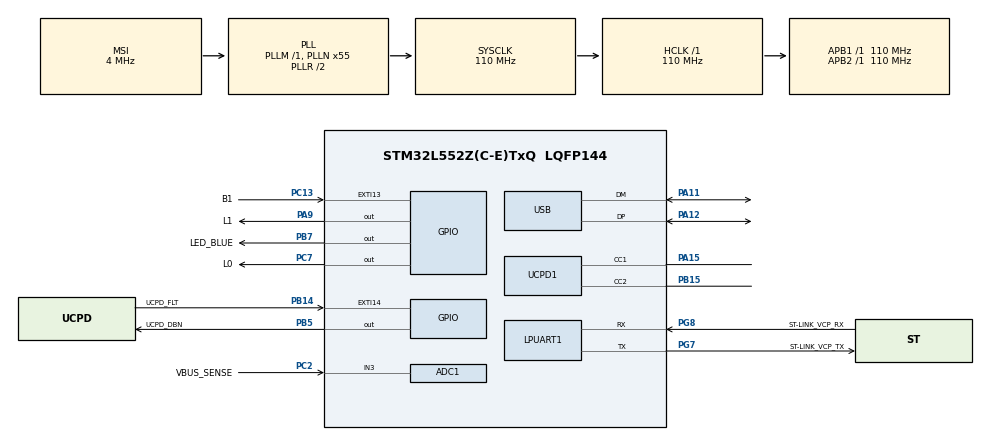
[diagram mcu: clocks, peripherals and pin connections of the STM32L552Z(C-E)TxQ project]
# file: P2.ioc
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ADC1.Channel-0\#ChannelRegularConversion=ADC_CHANNEL_3
ADC1.NbrOfConversionFlag=1
ADC1.OffsetNumber-0\#ChannelRegularConversion=ADC_OFFSET_NONE
ADC1.Rank-0\#ChannelRegularConversion=1
ADC1.SamplingTime-0\#ChannelRegularConversion=ADC_SAMPLETIME_2CYCLES_5
ADC1.master=1
Mcu.Family=STM32L5
Mcu.Name=STM32L552Z(C-E)TxQ
Mcu.Package=LQFP144
Mcu.TrustZone=disable
NVIC.EXTI13_IRQn=true\:0\:0\:false\:false\:true\:true\:true\:true
NVIC.PriorityGroup=NVIC_PRIORITYGROUP_3
PA11.Mode=Device
PA11.Signal=USB_DM
PA12.Mode=Device
PA12.Signal=USB_DP
PA13\ (JTMS/SWDIO).Mode=Trace_Asynchronous_SW
PA13\ (JTMS/SWDIO).Signal=DEBUG_JTMS-SWDIO
PA14\ (JTCK/SWCLK).Mode=Trace_Asynchronous_SW
PA14\ (JTCK/SWCLK).Signal=DEBUG_JTCK-SWCLK
PA15\ (JTDI).Mode=Source_AllSignals
PA15\ (JTDI).Signal=UCPD1_CC1
PA9.GPIO_Label=L1
PA9.Signal=GPIO_Output
PB14.GPIO_Label=UCPD_FLT
PB14.Signal=GPXTI14
PB15.Mode=Source_AllSignals
PB15.Signal=UCPD1_CC2
PB3\ (JTDO/TRACESWO).Mode=Trace_Asynchronous_SW
PB3\ (JTDO/TRACESWO).Signal=DEBUG_JTDO-SWO
PB5.GPIO_Label=UCPD_DBN
PB5.Signal=GPIO_Output
PB7.GPIO_Label=LED_BLUE
PB7.Signal=GPIO_Output
PC13.GPIO_Label=B1
PC13.Signal=GPXTI13
PC14-OSC32_IN\ (PC14).Mode=LSE-External-Oscillator
PC14-OSC32_IN\ (PC14).Signal=RCC_OSC32_IN
PC15-OSC32_OUT\ (PC15).Mode=LSE-External-Oscillator
PC15-OSC32_OUT\ (PC15).Signal=RCC_OSC32_OUT
PC2.GPIO_Label=VBUS_SENSE
PC2.Signal=ADCx_IN3
PC7.GPIO_Label=L0
PC7.Signal=GPIO_Output
PG7.GPIO_Label=ST-LINK_VCP_TX
PG7.Mode=Asynchronous
PG7.Signal=LPUART1_TX
PG8.GPIO_Label=ST-LINK_VCP_RX
PG8.Mode=Asynchronous
PG8.Signal=LPUART1_RX
ProjectManager.HeapSize=0x200
ProjectManager.StackSize=0x400
ProjectManager.TargetToolchain=STM32CubeIDE
RCC.ADCCLockSelection=RCC_ADCCLKSOURCE_SYSCLK
RCC.ADCFreq_Value=110000000
RCC.AHBFreq_Value=110000000
RCC.APB1Freq_Value=110000000
RCC.APB1TimFreq_Value=110000000
RCC.APB2Freq_Value=110000000
RCC.APB2TimFreq_Value=110000000
RCC.CK48CLockSelection=RCC_USBCLKSOURCE_HSI48
RCC.CortexFreq_Value=110000000
RCC.HCLKFreq_Value=110000000
RCC.HSE_VALUE=8000000
RCC.HSI48_VALUE=48000000
RCC.HSI_VALUE=16000000
RCC.MSI_VALUE=4000000
RCC.PLLN=55
RCC.PLLSAI1N=24
RCC.RTCClockSelection=RCC_RTCCLKSOURCE_LSE
RCC.SYSCLKFreq_VALUE=110000000
RCC.SYSCLKSource=RCC_SYSCLKSOURCE_PLLCLK
RCC.USBFreq_Value=48000000
RCC.VCOOutputFreq_Value=220000000
SH.ADCx_IN3.0=ADC1_IN3,IN3-Single-Ended
VP_ICACHE_VS_ICACHE.Mode=DirectMappedCache
VP_PWR_VS_DBSignals.Mode=DisableDeadBatterySignals
VP_RTC_VS_RTC_Activate.Mode=RTC_Enabled
board=NUCLEO-L552ZE-Q

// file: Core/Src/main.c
/* USER CODE BEGIN Header */
/**
  ******************************************************************************
  * @file           : main.c
  * @brief          : Main program body
  ******************************************************************************
  * @attention
  *
  * Copyright (c) 2024 STMicroelectronics.
  * All rights reserved.
  *
  * This software is licensed under terms that can be found in the LICENSE file
  * in the root directory of this software component.
  * If no LICENSE file comes with this software, it is provided AS-IS.
  *
  ******************************************************************************
  */
/* USER CODE END Header */
#include "main.h"

ADC_HandleTypeDef hadc1;

UART_HandleTypeDef hlpuart1;

RTC_HandleTypeDef hrtc;

PCD_HandleTypeDef hpcd_USB_FS;

/* USER CODE BEGIN PV */

uint8_t interrupcion0=0; //var que refleJa la interrupcion causada por la activacion de B0

uint8_t interrupcion1=0;//var que refleJa la interrupcion causada por la activacion de B1

int estado = 0; //var para almacenar estado en el que  se encuentra la ejecucion

/* USER CODE END PV */

void SystemClock_Config(void);
static void MX_GPIO_Init(void);
static void MX_ADC1_Init(void);
static void MX_ICACHE_Init(void);
static void MX_LPUART1_UART_Init(void);
static void MX_RTC_Init(void);
static void MX_UCPD1_Init(void);
static void MX_USB_PCD_Init(void);

int main(void)
{

  /* MCU Configuration--------------------------------------------------------*/

  /* Reset of all peripherals, Initializes the Flash interface and the Systick. */
  HAL_Init();

  /* Configure the system clock */
  SystemClock_Config();

  /* Initialize all configured peripherals */
  MX_GPIO_Init();
  MX_ADC1_Init();
  MX_ICACHE_Init();
  MX_LPUART1_UART_Init();
  MX_RTC_Init();
  MX_UCPD1_Init();
  MX_USB_PCD_Init();

  /* Infinite loop */
  /* USER CODE BEGIN WHILE */
  while (1)
  {
	  //cambios de estado segun estado actual para B0=1; B1=0
	  if(interrupcion0==1){
		  if(estado==0){
			  estado=3;
		  }else if(estado==1){
			  estado=0;
		  }else if(estado==2){
			  estado=1;
		  }else if(estado==3){
			  estado=2;
		  }
		  interrupcion0=0;

	  }else if(interrupcion1==1){//cambios de estado segun estado actual para B0=0; B1=1

		  if(estado==0){
			  estado=1;
		  }else if(estado==1){
			  estado=2;
		  }else if(estado==2){
			  estado=3;
		  }else if(estado==3){
			  estado=0;
		  }
		  interrupcion1=0;

	  }

	  //acciones para cada estado
	  if(estado==0){
		  //L0=0; L1=1
		  HAL_GPIO_WritePin(L0_GPIO_Port, L0_Pin, GPIO_PIN_RESET);
		  HAL_GPIO_WritePin(L1_GPIO_Port, L1_Pin, GPIO_PIN_SET);

	  }else if(estado==1){
		  //L0=1; L1=0
		  HAL_GPIO_WritePin(L0_GPIO_Port, L0_Pin, GPIO_PIN_SET);
		  HAL_GPIO_WritePin(L1_GPIO_Port, L1_Pin, GPIO_PIN_RESET);

	  }else if(estado==2){
		  //L0=1; L1=1
		  HAL_GPIO_WritePin(L0_GPIO_Port, L0_Pin, GPIO_PIN_SET);
		  HAL_GPIO_WritePin(L1_GPIO_Port, L1_Pin, GPIO_PIN_SET);

	  }else if(estado==3){
		  //L0=0; L1=0
		  HAL_GPIO_WritePin(L0_GPIO_Port, L0_Pin, GPIO_PIN_RESET);
		  HAL_GPIO_WritePin(L1_GPIO_Port, L1_Pin, GPIO_PIN_RESET);

	  }
    /* USER CODE END WHILE */

  }
}

void SystemClock_Config(void)
{
  RCC_OscInitTypeDef RCC_OscInitStruct = {0};
  RCC_ClkInitTypeDef RCC_ClkInitStruct = {0};

  /** Configure the main internal regulator output voltage
  */
  if (HAL_PWREx_ControlVoltageScaling(PWR_REGULATOR_VOLTAGE_SCALE0) != HAL_OK)
  {
    Error_Handler();
  }

  /** Configure LSE Drive Capability
  */
  HAL_PWR_EnableBkUpAccess();
  __HAL_RCC_LSEDRIVE_CONFIG(RCC_LSEDRIVE_LOW);

  /** Initializes the RCC Oscillators according to the specified parameters
  * in the RCC_OscInitTypeDef structure.
  */
  RCC_OscInitStruct.OscillatorType = RCC_OSCILLATORTYPE_HSI48|RCC_OSCILLATORTYPE_HSI
                              |RCC_OSCILLATORTYPE_LSE|RCC_OSCILLATORTYPE_MSI;
  RCC_OscInitStruct.LSEState = RCC_LSE_ON;
  RCC_OscInitStruct.HSIState = RCC_HSI_ON;
  RCC_OscInitStruct.HSI48State = RCC_HSI48_ON;
  RCC_OscInitStruct.HSICalibrationValue = RCC_HSICALIBRATION_DEFAULT;
  RCC_OscInitStruct.MSIState = RCC_MSI_ON;
  RCC_OscInitStruct.MSICalibrationValue = RCC_MSICALIBRATION_DEFAULT;
  RCC_OscInitStruct.MSIClockRange = RCC_MSIRANGE_6;
  RCC_OscInitStruct.PLL.PLLState = RCC_PLL_ON;
  RCC_OscInitStruct.PLL.PLLSource = RCC_PLLSOURCE_MSI;
  RCC_OscInitStruct.PLL.PLLM = 1;
  RCC_OscInitStruct.PLL.PLLN = 55;
  RCC_OscInitStruct.PLL.PLLP = RCC_PLLP_DIV7;
  RCC_OscInitStruct.PLL.PLLQ = RCC_PLLQ_DIV2;
  RCC_OscInitStruct.PLL.PLLR = RCC_PLLR_DIV2;
  if (HAL_RCC_OscConfig(&RCC_OscInitStruct) != HAL_OK)
  {
    Error_Handler();
  }

  /** Initializes the CPU, AHB and APB buses clocks
  */
  RCC_ClkInitStruct.ClockType = RCC_CLOCKTYPE_HCLK|RCC_CLOCKTYPE_SYSCLK
                              |RCC_CLOCKTYPE_PCLK1|RCC_CLOCKTYPE_PCLK2;
  RCC_ClkInitStruct.SYSCLKSource = RCC_SYSCLKSOURCE_PLLCLK;
  RCC_ClkInitStruct.AHBCLKDivider = RCC_SYSCLK_DIV1;
  RCC_ClkInitStruct.APB1CLKDivider = RCC_HCLK_DIV1;
  RCC_ClkInitStruct.APB2CLKDivider = RCC_HCLK_DIV1;

  if (HAL_RCC_ClockConfig(&RCC_ClkInitStruct, FLASH_LATENCY_5) != HAL_OK)
  {
    Error_Handler();
  }
}

static void MX_ADC1_Init(void)
{

  ADC_MultiModeTypeDef multimode = {0};
  ADC_ChannelConfTypeDef sConfig = {0};

  /** Common config
  */
  hadc1.Instance = ADC1;
  hadc1.Init.ClockPrescaler = ADC_CLOCK_ASYNC_DIV1;
  hadc1.Init.Resolution = ADC_RESOLUTION_12B;
  hadc1.Init.DataAlign = ADC_DATAALIGN_RIGHT;
  hadc1.Init.ScanConvMode = ADC_SCAN_DISABLE;
  hadc1.Init.EOCSelection = ADC_EOC_SINGLE_CONV;
  hadc1.Init.LowPowerAutoWait = DISABLE;
  hadc1.Init.ContinuousConvMode = DISABLE;
  hadc1.Init.NbrOfConversion = 1;
  hadc1.Init.DiscontinuousConvMode = DISABLE;
  hadc1.Init.ExternalTrigConv = ADC_SOFTWARE_START;
  hadc1.Init.ExternalTrigConvEdge = ADC_EXTERNALTRIGCONVEDGE_NONE;
  hadc1.Init.DMAContinuousRequests = DISABLE;
  hadc1.Init.Overrun = ADC_OVR_DATA_PRESERVED;
  hadc1.Init.OversamplingMode = DISABLE;
  if (HAL_ADC_Init(&hadc1) != HAL_OK)
  {
    Error_Handler();
  }

  /** Configure the ADC multi-mode
  */
  multimode.Mode = ADC_MODE_INDEPENDENT;
  if (HAL_ADCEx_MultiModeConfigChannel(&hadc1, &multimode) != HAL_OK)
  {
    Error_Handler();
  }

  /** Configure Regular Channel
  */
  sConfig.Channel = ADC_CHANNEL_3;
  sConfig.Rank = ADC_REGULAR_RANK_1;
  sConfig.SamplingTime = ADC_SAMPLETIME_2CYCLES_5;
  sConfig.SingleDiff = ADC_SINGLE_ENDED;
  sConfig.OffsetNumber = ADC_OFFSET_NONE;
  sConfig.Offset = 0;
  if (HAL_ADC_ConfigChannel(&hadc1, &sConfig) != HAL_OK)
  {
    Error_Handler();
  }

}

static void MX_ICACHE_Init(void)
{

  /** Enable instruction cache in 1-way (direct mapped cache)
  */
  if (HAL_ICACHE_ConfigAssociativityMode(ICACHE_1WAY) != HAL_OK)
  {
    Error_Handler();
  }
  if (HAL_ICACHE_Enable() != HAL_OK)
  {
    Error_Handler();
  }

}

static void MX_LPUART1_UART_Init(void)
{

  hlpuart1.Instance = LPUART1;
  hlpuart1.Init.BaudRate = 209700;
  hlpuart1.Init.WordLength = UART_WORDLENGTH_8B;
  hlpuart1.Init.StopBits = UART_STOPBITS_1;
  hlpuart1.Init.Parity = UART_PARITY_NONE;
  hlpuart1.Init.Mode = UART_MODE_TX_RX;
  hlpuart1.Init.HwFlowCtl = UART_HWCONTROL_NONE;
  hlpuart1.Init.OneBitSampling = UART_ONE_BIT_SAMPLE_DISABLE;
  hlpuart1.Init.ClockPrescaler = UART_PRESCALER_DIV1;
  hlpuart1.AdvancedInit.AdvFeatureInit = UART_ADVFEATURE_NO_INIT;
  hlpuart1.FifoMode = UART_FIFOMODE_DISABLE;
  if (HAL_UART_Init(&hlpuart1) != HAL_OK)
  {
    Error_Handler();
  }
  if (HAL_UARTEx_SetTxFifoThreshold(&hlpuart1, UART_TXFIFO_THRESHOLD_1_8) != HAL_OK)
  {
    Error_Handler();
  }
  if (HAL_UARTEx_SetRxFifoThreshold(&hlpuart1, UART_RXFIFO_THRESHOLD_1_8) != HAL_OK)
  {
    Error_Handler();
  }
  if (HAL_UARTEx_DisableFifoMode(&hlpuart1) != HAL_OK)
  {
    Error_Handler();
  }

}

static void MX_RTC_Init(void)
{

  RTC_PrivilegeStateTypeDef privilegeState = {0};

  /** Initialize RTC Only
  */
  hrtc.Instance = RTC;
  hrtc.Init.HourFormat = RTC_HOURFORMAT_24;
  hrtc.Init.AsynchPrediv = 127;
  hrtc.Init.SynchPrediv = 255;
  hrtc.Init.OutPut = RTC_OUTPUT_DISABLE;
  hrtc.Init.OutPutRemap = RTC_OUTPUT_REMAP_NONE;
  hrtc.Init.OutPutPolarity = RTC_OUTPUT_POLARITY_HIGH;
  hrtc.Init.OutPutType = RTC_OUTPUT_TYPE_OPENDRAIN;
  hrtc.Init.OutPutPullUp = RTC_OUTPUT_PULLUP_NONE;
  if (HAL_RTC_Init(&hrtc) != HAL_OK)
  {
    Error_Handler();
  }
  privilegeState.rtcPrivilegeFull = RTC_PRIVILEGE_FULL_NO;
  privilegeState.backupRegisterPrivZone = RTC_PRIVILEGE_BKUP_ZONE_NONE;
  privilegeState.backupRegisterStartZone2 = RTC_BKP_DR0;
  privilegeState.backupRegisterStartZone3 = RTC_BKP_DR0;
  if (HAL_RTCEx_PrivilegeModeSet(&hrtc, &privilegeState) != HAL_OK)
  {
    Error_Handler();
  }

}

static void MX_UCPD1_Init(void)
{

  LL_GPIO_InitTypeDef GPIO_InitStruct = {0};

  /* Peripheral clock enable */
  LL_APB1_GRP2_EnableClock(LL_APB1_GRP2_PERIPH_UCPD1);

  LL_AHB2_GRP1_EnableClock(LL_AHB2_GRP1_PERIPH_GPIOB);
  LL_AHB2_GRP1_EnableClock(LL_AHB2_GRP1_PERIPH_GPIOA);
  /**UCPD1 GPIO Configuration
  PB15   ------> UCPD1_CC2
  PA15 (JTDI)   ------> UCPD1_CC1
  */
  GPIO_InitStruct.Pin = LL_GPIO_PIN_15;
  GPIO_InitStruct.Mode = LL_GPIO_MODE_ANALOG;
  GPIO_InitStruct.Pull = LL_GPIO_PULL_NO;
  LL_GPIO_Init(GPIOB, &GPIO_InitStruct);

  GPIO_InitStruct.Pin = LL_GPIO_PIN_15;
  GPIO_InitStruct.Mode = LL_GPIO_MODE_ANALOG;
  GPIO_InitStruct.Pull = LL_GPIO_PULL_NO;
  LL_GPIO_Init(GPIOA, &GPIO_InitStruct);

}

static void MX_USB_PCD_Init(void)
{

  hpcd_USB_FS.Instance = USB;
  hpcd_USB_FS.Init.dev_endpoints = 8;
  hpcd_USB_FS.Init.speed = PCD_SPEED_FULL;
  hpcd_USB_FS.Init.phy_itface = PCD_PHY_EMBEDDED;
  hpcd_USB_FS.Init.Sof_enable = DISABLE;
  hpcd_USB_FS.Init.low_power_enable = DISABLE;
  hpcd_USB_FS.Init.lpm_enable = DISABLE;
  hpcd_USB_FS.Init.battery_charging_enable = DISABLE;
  if (HAL_PCD_Init(&hpcd_USB_FS) != HAL_OK)
  {
    Error_Handler();
  }

}

static void MX_GPIO_Init(void)
{
  GPIO_InitTypeDef GPIO_InitStruct = {0};

  /* GPIO Ports Clock Enable */
  __HAL_RCC_GPIOC_CLK_ENABLE();
  __HAL_RCC_GPIOB_CLK_ENABLE();
  __HAL_RCC_GPIOG_CLK_ENABLE();
  HAL_PWREx_EnableVddIO2();
  __HAL_RCC_GPIOA_CLK_ENABLE();

  /*Configure GPIO pin Output Level */
  HAL_GPIO_WritePin(L0_GPIO_Port, L0_Pin, GPIO_PIN_RESET);

  /*Configure GPIO pin Output Level */
  HAL_GPIO_WritePin(LED_RED_GPIO_Port, LED_RED_Pin, GPIO_PIN_RESET);

  /*Configure GPIO pin Output Level */
  HAL_GPIO_WritePin(GPIOB, UCPD_DBN_Pin|L1_Pin, GPIO_PIN_RESET);

  /*Configure GPIO pin : B0_Pin */
  GPIO_InitStruct.Pin = B0_Pin;
  GPIO_InitStruct.Mode = GPIO_MODE_IT_RISING;
  GPIO_InitStruct.Pull = GPIO_NOPULL;
  HAL_GPIO_Init(B0_GPIO_Port, &GPIO_InitStruct);

  /*Configure GPIO pin : UCPD_FLT_Pin */
  GPIO_InitStruct.Pin = UCPD_FLT_Pin;
  GPIO_InitStruct.Mode = GPIO_MODE_IT_RISING;
  GPIO_InitStruct.Pull = GPIO_NOPULL;
  HAL_GPIO_Init(UCPD_FLT_GPIO_Port, &GPIO_InitStruct);

  /*Configure GPIO pin : L0_Pin */
  GPIO_InitStruct.Pin = L0_Pin;
  GPIO_InitStruct.Mode = GPIO_MODE_OUTPUT_PP;
  GPIO_InitStruct.Pull = GPIO_NOPULL;
  GPIO_InitStruct.Speed = GPIO_SPEED_FREQ_LOW;
  HAL_GPIO_Init(L0_GPIO_Port, &GPIO_InitStruct);

  /*Configure GPIO pin : LED_RED_Pin */
  GPIO_InitStruct.Pin = LED_RED_Pin;
  GPIO_InitStruct.Mode = GPIO_MODE_OUTPUT_PP;
  GPIO_InitStruct.Pull = GPIO_NOPULL;
  GPIO_InitStruct.Speed = GPIO_SPEED_FREQ_LOW;
  HAL_GPIO_Init(LED_RED_GPIO_Port, &GPIO_InitStruct);

  /*Configure GPIO pins : UCPD_DBN_Pin L1_Pin */
  GPIO_InitStruct.Pin = UCPD_DBN_Pin|L1_Pin;
  GPIO_InitStruct.Mode = GPIO_MODE_OUTPUT_PP;
  GPIO_InitStruct.Pull = GPIO_NOPULL;
  GPIO_InitStruct.Speed = GPIO_SPEED_FREQ_LOW;
  HAL_GPIO_Init(GPIOB, &GPIO_InitStruct);

  /*Configure GPIO pin : B1_Pin */
  GPIO_InitStruct.Pin = B1_Pin;
  GPIO_InitStruct.Mode = GPIO_MODE_IT_RISING;
  GPIO_InitStruct.Pull = GPIO_PULLDOWN;
  HAL_GPIO_Init(B1_GPIO_Port, &GPIO_InitStruct);

  /* EXTI interrupt init*/
  HAL_NVIC_SetPriority(EXTI8_IRQn, 0, 0);
  HAL_NVIC_EnableIRQ(EXTI8_IRQn);

  HAL_NVIC_SetPriority(EXTI13_IRQn, 0, 0);
  HAL_NVIC_EnableIRQ(EXTI13_IRQn);

}

/* USER CODE BEGIN 4 */
void HAL_GPIO_EXTI_Rising_Callback(uint16_t GPIO_Pin)
{
	//Almacenamiento de la interrupccion segun la fuente de su causa
	if (GPIO_Pin == B0_Pin){
		interrupcion0 = 1;

	}else {
		interrupcion1 = 1;
	}

}

/* USER CODE END 4 */

void Error_Handler(void)
{
  __disable_irq();
  while (1)
  {
  }
}
